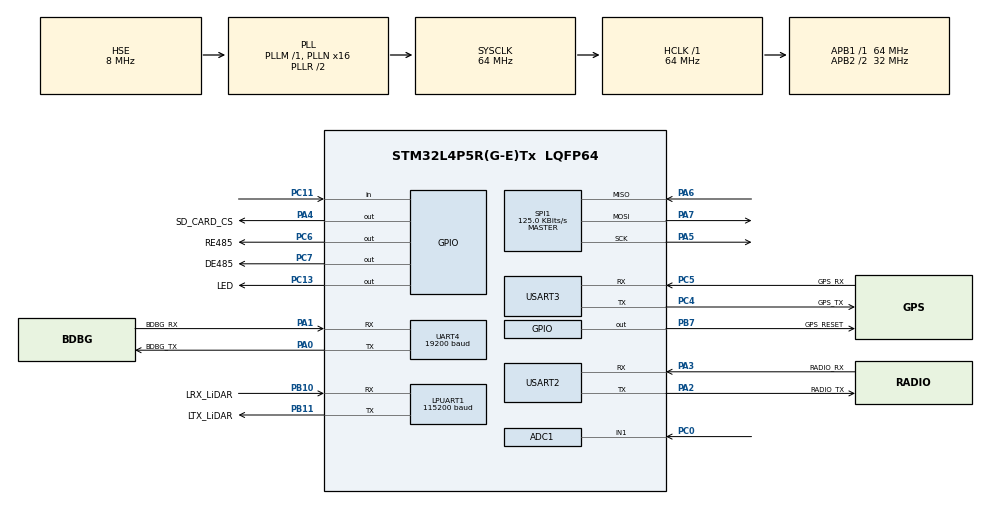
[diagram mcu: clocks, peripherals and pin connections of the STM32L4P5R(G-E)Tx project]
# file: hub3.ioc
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ADC1.Channel-2\#ChannelRegularConversion=ADC_CHANNEL_1
ADC1.NbrOfConversionFlag=1
ADC1.OffsetNumber-2\#ChannelRegularConversion=ADC_OFFSET_NONE
ADC1.Rank-2\#ChannelRegularConversion=1
ADC1.SamplingTime-2\#ChannelRegularConversion=ADC_SAMPLETIME_2CYCLES_5
ADC1.master=1
Dma.LPUART1_RX.2.Direction=DMA_PERIPH_TO_MEMORY
Dma.LPUART1_RX.2.EventEnable=DISABLE
Dma.LPUART1_RX.2.Instance=DMA2_Channel3
Dma.LPUART1_RX.2.MemDataAlignment=DMA_MDATAALIGN_BYTE
Dma.LPUART1_RX.2.MemInc=DMA_MINC_ENABLE
Dma.LPUART1_RX.2.Mode=DMA_CIRCULAR
Dma.LPUART1_RX.2.PeriphDataAlignment=DMA_PDATAALIGN_BYTE
Dma.LPUART1_RX.2.PeriphInc=DMA_PINC_DISABLE
Dma.LPUART1_RX.2.Polarity=HAL_DMAMUX_REQ_GEN_RISING
Dma.LPUART1_RX.2.Priority=DMA_PRIORITY_LOW
Dma.LPUART1_RX.2.RequestNumber=1
Dma.LPUART1_RX.2.SignalID=NONE
Dma.LPUART1_RX.2.SyncEnable=DISABLE
Dma.LPUART1_RX.2.SyncPolarity=HAL_DMAMUX_SYNC_NO_EVENT
Dma.LPUART1_RX.2.SyncRequestNumber=1
Dma.LPUART1_RX.2.SyncSignalID=NONE
Dma.Request0=USART3_RX
Dma.Request1=UART4_RX
Dma.Request2=LPUART1_RX
Dma.Request3=USART2_RX
Dma.UART4_RX.1.Direction=DMA_PERIPH_TO_MEMORY
Dma.UART4_RX.1.EventEnable=DISABLE
Dma.UART4_RX.1.Instance=DMA2_Channel2
Dma.UART4_RX.1.MemDataAlignment=DMA_MDATAALIGN_BYTE
Dma.UART4_RX.1.MemInc=DMA_MINC_ENABLE
Dma.UART4_RX.1.Mode=DMA_NORMAL
Dma.UART4_RX.1.PeriphDataAlignment=DMA_PDATAALIGN_BYTE
Dma.UART4_RX.1.PeriphInc=DMA_PINC_DISABLE
Dma.UART4_RX.1.Polarity=HAL_DMAMUX_REQ_GEN_RISING
Dma.UART4_RX.1.Priority=DMA_PRIORITY_LOW
Dma.UART4_RX.1.RequestNumber=1
Dma.UART4_RX.1.SignalID=NONE
Dma.UART4_RX.1.SyncEnable=DISABLE
Dma.UART4_RX.1.SyncPolarity=HAL_DMAMUX_SYNC_NO_EVENT
Dma.UART4_RX.1.SyncRequestNumber=1
Dma.UART4_RX.1.SyncSignalID=NONE
Dma.USART2_RX.3.Direction=DMA_PERIPH_TO_MEMORY
Dma.USART2_RX.3.EventEnable=DISABLE
Dma.USART2_RX.3.Instance=DMA2_Channel5
Dma.USART2_RX.3.MemDataAlignment=DMA_MDATAALIGN_BYTE
Dma.USART2_RX.3.MemInc=DMA_MINC_ENABLE
Dma.USART2_RX.3.Mode=DMA_CIRCULAR
Dma.USART2_RX.3.PeriphDataAlignment=DMA_PDATAALIGN_BYTE
Dma.USART2_RX.3.PeriphInc=DMA_PINC_DISABLE
Dma.USART2_RX.3.Polarity=HAL_DMAMUX_REQ_GEN_RISING
Dma.USART2_RX.3.Priority=DMA_PRIORITY_LOW
Dma.USART2_RX.3.RequestNumber=1
Dma.USART2_RX.3.SignalID=NONE
Dma.USART2_RX.3.SyncEnable=DISABLE
Dma.USART2_RX.3.SyncPolarity=HAL_DMAMUX_SYNC_NO_EVENT
Dma.USART2_RX.3.SyncRequestNumber=1
Dma.USART2_RX.3.SyncSignalID=NONE
Dma.USART3_RX.0.Direction=DMA_PERIPH_TO_MEMORY
Dma.USART3_RX.0.EventEnable=DISABLE
Dma.USART3_RX.0.Instance=DMA2_Channel1
Dma.USART3_RX.0.MemDataAlignment=DMA_MDATAALIGN_BYTE
Dma.USART3_RX.0.MemInc=DMA_MINC_ENABLE
Dma.USART3_RX.0.Mode=DMA_CIRCULAR
Dma.USART3_RX.0.PeriphDataAlignment=DMA_PDATAALIGN_BYTE
Dma.USART3_RX.0.PeriphInc=DMA_PINC_DISABLE
Dma.USART3_RX.0.Polarity=HAL_DMAMUX_REQ_GEN_RISING
Dma.USART3_RX.0.Priority=DMA_PRIORITY_LOW
Dma.USART3_RX.0.RequestNumber=1
Dma.USART3_RX.0.SignalID=NONE
Dma.USART3_RX.0.SyncEnable=DISABLE
Dma.USART3_RX.0.SyncPolarity=HAL_DMAMUX_SYNC_NO_EVENT
Dma.USART3_RX.0.SyncRequestNumber=1
Dma.USART3_RX.0.SyncSignalID=NONE
LPUART1.BaudRate=115200
LPUART1.WordLength=UART_WORDLENGTH_8B
Mcu.Family=STM32L4
Mcu.Name=STM32L4P5R(G-E)Tx
Mcu.Package=LQFP64
NVIC.DMA2_Channel1_IRQn=true\:0\:0\:false\:false\:true\:false\:true\:true
NVIC.DMA2_Channel2_IRQn=true\:0\:0\:false\:false\:true\:false\:true\:true
NVIC.DMA2_Channel3_IRQn=true\:0\:0\:false\:false\:true\:false\:true\:true
NVIC.DMA2_Channel5_IRQn=true\:0\:0\:false\:false\:true\:false\:true\:true
NVIC.LPUART1_IRQn=true\:0\:0\:false\:false\:true\:true\:true\:true
NVIC.PriorityGroup=NVIC_PRIORITYGROUP_4
NVIC.RTC_WKUP_IRQn=true\:0\:0\:false\:false\:true\:true\:true\:true
NVIC.TIM3_IRQn=true\:0\:0\:false\:false\:true\:true\:true\:true
NVIC.TIM6_DAC_IRQn=true\:1\:0\:true\:false\:true\:true\:true\:true
NVIC.UART4_IRQn=true\:0\:0\:false\:false\:true\:true\:true\:true
NVIC.USART2_IRQn=true\:0\:0\:false\:false\:true\:true\:true\:true
NVIC.USART3_IRQn=true\:0\:0\:false\:false\:true\:true\:true\:true
PA0.GPIO_Label=BDBG_TX
PA0.Mode=Asynchronous
PA0.Signal=UART4_TX
PA1.GPIO_Label=BDBG_RX
PA1.Mode=Asynchronous
PA1.Signal=UART4_RX
PA2.GPIO_Label=RADIO_TX
PA2.Mode=Asynchronous
PA2.Signal=USART2_TX
PA3.GPIO_Label=RADIO_RX
PA3.Mode=Asynchronous
PA3.Signal=USART2_RX
PA4.GPIO_Label=SD_CARD_CS
PA4.GPIO_PuPd=GPIO_PULLUP
PA4.PinState=GPIO_PIN_SET
PA4.Signal=GPIO_Output
PA5.GPIO_PuPd=GPIO_PULLUP
PA5.Mode=Full_Duplex_Master
PA5.Signal=SPI1_SCK
PA6.GPIO_PuPd=GPIO_PULLUP
PA6.Mode=Full_Duplex_Master
PA6.Signal=SPI1_MISO
PA7.GPIO_PuPd=GPIO_PULLUP
PA7.Mode=Full_Duplex_Master
PA7.Signal=SPI1_MOSI
PB10.GPIO_Label=LRX_LiDAR
PB10.Mode=Asynchronous
PB10.Signal=LPUART1_RX
PB11.GPIO_Label=LTX_LiDAR
PB11.Mode=Asynchronous
PB11.Signal=LPUART1_TX
PB7.GPIO_Label=GPS_RESET
PB7.Signal=GPIO_Output
PC0.Signal=ADCx_IN1
PC11.Signal=GPIO_Input
PC13.GPIO_Label=LED
PC13.Signal=GPIO_Output
PC4.GPIO_Label=GPS_TX
PC4.Mode=Asynchronous
PC4.Signal=USART3_TX
PC5.GPIO_Label=GPS_RX
PC5.Mode=Asynchronous
PC5.Signal=USART3_RX
PC6.GPIO_Label=RE485
PC6.Signal=GPIO_Output
PC7.GPIO_Label=DE485
PC7.Signal=GPIO_Output
PH0-OSC_IN\ (PH0).Mode=HSE-External-Oscillator
PH0-OSC_IN\ (PH0).Signal=RCC_OSC_IN
PH1-OSC_OUT\ (PH1).Mode=HSE-External-Oscillator
PH1-OSC_OUT\ (PH1).Signal=RCC_OSC_OUT
ProjectManager.HeapSize=0x8000
ProjectManager.StackSize=0x8000
ProjectManager.TargetToolchain=MDK-ARM V5.32
RCC.ADCFreq_Value=32000000
RCC.AHBFreq_Value=64000000
RCC.APB1Freq_Value=64000000
RCC.APB1TimFreq_Value=64000000
RCC.APB2CLKDivider=RCC_HCLK_DIV2
RCC.APB2Freq_Value=32000000
RCC.APB2TimFreq_Value=64000000
RCC.CortexFreq_Value=64000000
RCC.HCLKFreq_Value=64000000
RCC.HSE_VALUE=8000000
RCC.HSI48_VALUE=48000000
RCC.HSI_VALUE=16000000
RCC.LSE_VALUE=32768
RCC.MSI_VALUE=4000000
RCC.PLLN=16
RCC.PLLSourceVirtual=RCC_PLLSOURCE_HSE
RCC.SYSCLKFreq_VALUE=64000000
RCC.SYSCLKSource=RCC_SYSCLKSOURCE_PLLCLK
RCC.USBFreq_Value=32000000
RCC.VCOOutputFreq_Value=128000000
RTC.WakeUpClock-WakeUp=RTC_WAKEUPCLOCK_CK_SPRE_16BITS
RTC.WakeUpCounter-WakeUp=59
SH.ADCx_IN1.0=ADC1_IN1,IN1-Single-Ended
SPI1.BaudRatePrescaler=SPI_BAUDRATEPRESCALER_256
SPI1.CalculateBaudRate=125.0 KBits/s
SPI1.DataSize=SPI_DATASIZE_8BIT
SPI1.Direction=SPI_DIRECTION_2LINES
SPI1.Mode=SPI_MODE_MASTER
SPI1.VirtualType=VM_MASTER
TIM3.Period=4999
TIM3.Prescaler=63999
TIM6.Period=99
TIM6.Prescaler=63999
UART4.BaudRate=19200
USART2.VirtualMode-Asynchronous=VM_ASYNC
USART3.VirtualMode-Asynchronous=VM_ASYNC
VP_FATFS_VS_Generic.Mode=User_defined
VP_RTC_VS_RTC_Activate.Mode=RTC_Enabled
VP_RTC_VS_RTC_Calendar.Mode=RTC_Calendar
VP_RTC_VS_RTC_WakeUp_intern.Mode=WakeUp
VP_TIM3_VS_ClockSourceINT.Mode=Internal
VP_TIM3_VS_OPM.Mode=OPM_bit
VP_TIM6_VS_ClockSourceINT.Mode=Enable_Timer
board=custom

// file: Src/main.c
/* USER CODE BEGIN Header */
/**
  ******************************************************************************
  * @file           : main.c
  * @brief          : Main program body
  ******************************************************************************
  * @attention
  *
  * Copyright (c) 2026 STMicroelectronics.
  * All rights reserved.
  *
  * This software is licensed under terms that can be found in the LICENSE file
  * in the root directory of this software component.
  * If no LICENSE file comes with this software, it is provided AS-IS.
  *
  ******************************************************************************
  */
/* USER CODE END Header */
#include "main.h"
#include "fatfs.h"

/* USER CODE BEGIN Includes */
#include <string.h>
#include <stdio.h>
#include "logger_types.h"
#include "logger_state_machine.h"
#include "gps.h"
#include "lidar.h"
#include "bdbg.h"
#include "bdbg_config.h"
#include "sd_logger.h"

/* USER CODE END Includes */

/* USER CODE BEGIN PD */

/*
 * Параметры первичной проверки аккумулятора.
 *
 * Напряжения указаны непосредственно на входе ADC1 (PC1),
 * до пересчёта через делитель напряжения.
 */
#define BATTERY_ADC_REFERENCE_V       2.5f
#define BATTERY_ADC_MAX_VALUE         4095.0f
#define BATTERY_STARTUP_SAMPLES       10U

#define BATTERY_THRESHOLD_33_V        0.824f
#define BATTERY_THRESHOLD_66_V        0.855f
#define BATTERY_THRESHOLD_100_V       0.915f

/* Максимальное ожидание одного преобразования ADC, мс. */
#define BATTERY_ADC_TIMEOUT_MS        100U

/* Время отображения результатов первичной проверки, мс. */
#define STARTUP_INDICATION_TIME_MS    60000U

/* USER CODE END PD */

ADC_HandleTypeDef hadc1;
DMA_HandleTypeDef hdma_adc1;

UART_HandleTypeDef hlpuart1;
UART_HandleTypeDef huart4;
UART_HandleTypeDef huart2;
UART_HandleTypeDef huart3;
DMA_HandleTypeDef hdma_lpuart1_rx;
DMA_HandleTypeDef hdma_uart4_rx;
DMA_HandleTypeDef hdma_usart2_rx;
DMA_HandleTypeDef hdma_usart3_rx;

RTC_HandleTypeDef hrtc;

SPI_HandleTypeDef hspi1;

TIM_HandleTypeDef htim3;
TIM_HandleTypeDef htim6;

/* USER CODE BEGIN PV */
uint16_t adc_value=0;

/*
 * ============================================================
 * РАБОЧИЕ ИЗМЕРЕНИЯ АККУМУЛЯТОРА
 * ============================================================
 *
 * Эти переменные используются для обмена данными
 * между прерыванием ADC1 и основной стейт-машиной.
 *
 * В отличие от первоначальной проверки аккумулятора,
 * рабочие измерения выполняются без блокирующего
 * ожидания завершения преобразования.
 */

/*
 * Результат последнего завершённого преобразования ADC1.
 *
 * Записывается обработчиком прерывания ADC.
 * Читается основной стейт-машиной.
 */
volatile uint16_t battery_adc_raw = 0U;

/*
 * Признак готовности очередного результата ADC.
 *
 * 0 — нового результата нет.
 * 1 — результат доступен в battery_adc_raw.
 *
 * После обработки результата флаг сбрасывается
 * основной стейт-машиной.
 */
volatile uint8_t battery_adc_ready = 0U;

/*
 * Признак ошибки ADC1.
 *
 * 0 — ошибка не зарегистрирована.
 * 1 — произошла ошибка ADC.
 *
 * Обработчик прерывания только устанавливает флаг.
 * Решение о переходе в BATTERY_ERROR_PROC
 * принимает основная стейт-машина.
 */
volatile uint8_t battery_adc_error = 0U;

/*
 * Разрешение обработки результатов рабочего
 * измерения аккумулятора.
 *
 * 0 — рабочее измерение не выполняется.
 * 1 — ADC используется состояниями аккумулятора.
 *
 * Это позволяет отделить рабочие измерения
 * от первоначальной проверки при запуске LOGGER.
 */
volatile uint8_t battery_adc_active = 0U;

/*
 * Основной объект стейт-машины LOGGER.
 * Содержит текущее состояние всей логики программы.
 */
LoggerStateMachine logger;

/*
 * Глобальный счётчик секунд RTC.
 *
 * Увеличивается на единицу при каждом прерывании
 * RTC WakeUp Timer (период 1 секунда).
 *
 * Значение никогда не обнуляется программой.
 * Основная стейт-машина только читает счётчик.
 *
 * volatile необходим, поскольку счётчик изменяется
 * в обработчике прерывания RTC.
 */
volatile uint32_t rtc_seconds = 0U;

/*
 * Размер DMA-буфера приёма USART2 (RadioLine).
 *
 * В этот буфер DMA непосредственно записывает байты,
 * поступающие по USART2.
 */
#define RADIOLINE_DMA_RX_BUFFER_SIZE    256U

/*
 * Размер общего буфера RadioLine.
 *
 * В него будем последовательно накапливать весь burst:
 * один пакет либо несколько подряд идущих копий пакета.
 *
 * Конкретный размер позже при необходимости скорректируем
 * по максимальному размеру команды протокола.
 */
#define RADIOLINE_RX_BUFFER_SIZE        2048U

/*
 * Рабочий буфер DMA для USART2.
 *
 * HAL_UARTEx_ReceiveToIdle_DMA() будет принимать сюда
 * очередную порцию данных от RadioLine.
 */
static uint8_t radioline_dma_rx_buffer[RADIOLINE_DMA_RX_BUFFER_SIZE];

/*
 * Общий накопительный буфер RadioLine.
 * После каждого события приёма данные из DMA-буфера
 * будут добавляться сюда. После 100 мс тишины этот
 * буфер будет готов к обработке в COMMAND_INFO.
 */
uint8_t radioline_rx_buffer[RADIOLINE_RX_BUFFER_SIZE];

/*
 * Текущее количество принятых байтов в общем
 * накопительном буфере RadioLine.
 */
volatile uint16_t radioline_rx_length = 0U;

/*
 * Флаг завершения приёма burst RadioLine.
 *
 * 0 - burst ещё принимается;
 * 1 - после последнего принятого байта прошло 100 мс.
 */
volatile uint8_t com_info = 0U;

/*
 * ============================================================================
 * Флаг срабатывания общего таймера контроля ответа прибора TIM3.
 *
 * TIM3 используется для ограничения времени ожидания ответа
 * от текущего прибора.
 *
 * Сам callback таймера НЕ принимает никаких решений и НЕ изменяет
 * состояние LOGGER. Он только устанавливает этот флаг.
 *
 * Обработка таймаута выполняется позже основной стейт-машиной,
 * которая по logger->dev_type определяет, ответ какого прибора ожидался.
 *
 * volatile необходим, поскольку значение изменяется из прерывания,
 * а читается из основного цикла программы.
 *
 * 0 - таймаут не произошёл;
 * 1 - время ожидания ответа прибора истекло.
 * ============================================================================
 */
volatile uint8_t device_timeout = 0U;

/* Буферы и управление GPS вынесены в gps.c. */

/* USER CODE END PV */

void SystemClock_Config(void);
static void MX_GPIO_Init(void);
static void MX_DMA_Init(void);
static void MX_USART3_UART_Init(void);
static void MX_USART2_UART_Init(void);
static void MX_SPI1_Init(void);
static void MX_ADC1_Init(void);
static void MX_UART4_Init(void);
static void MX_LPUART1_UART_Init(void);
static void MX_RTC_Init(void);
static void MX_TIM6_Init(void);
static void MX_TIM3_Init(void);
/* USER CODE BEGIN PFP */
/*
*/

#include <string.h>
#include <stdint.h>

void HAL_UARTEx_RxEventCallback(UART_HandleTypeDef *huart, uint16_t Size)
{
    /*
		 * Общий callback приёма данных UART.
		 *
		 * USART2 — приём команд RadioLine.
		 * USART3 — приём данных GPS.
		 *
		 * Обработка каждого интерфейса выполняется
		 * независимо от остальных.
		 */

		/*
		* Последняя обработанная позиция в циклическом DMA-буфере USART2.
		*
		* DMA USART2 работает в режиме DMA_CIRCULAR.
		* Поэтому после события IDLE DMA не перезапускается, а продолжает
		* записывать следующие байты дальше в radioline_dma_rx_buffer.
		*
		* Эта переменная позволяет определить, какие именно байты появились
		* с момента предыдущего вызова HAL_UARTEx_RxEventCallback().
		*/
		static uint16_t radioline_dma_old_pos = 0U;

		if (huart->Instance == USART2)
		{
				/*
				 * USART2 RX DMA работает в режиме DMA_CIRCULAR.
				 *
				 * В этом режиме параметр Size НЕ является просто размером
				 * очередной независимой порции данных.
				 *
				 * Size указывает текущую позицию DMA в циклическом буфере:
				 * данные доступны до позиции Size.
				 *
				 * Поэтому необходимо копировать только те байты,
				 * которые появились после предыдущего вызова callback.
				 */

				uint16_t new_data_length = 0U;

				/*
				 * СЛУЧАЙ 1.
				 *
				 * DMA ещё не дошёл до конца буфера.
				 *
				 * Например:
				 *
				 * radioline_dma_old_pos = 0
				 * Size                  = 14
				 *
				 * Значит новые данные находятся:
				 *
				 * radioline_dma_rx_buffer[0 ... 13]
				 */
				if (Size > radioline_dma_old_pos)
				{
						new_data_length = Size - radioline_dma_old_pos;

						/*
						 * Проверяем, помещаются ли новые данные
						 * в накопительный буфер RadioLine.
						 */
						if ((radioline_rx_length + new_data_length) <=
								RADIOLINE_RX_BUFFER_SIZE)
						{
								memcpy(&radioline_rx_buffer[radioline_rx_length],
											 &radioline_dma_rx_buffer[radioline_dma_old_pos],
											 new_data_length);

								radioline_rx_length += new_data_length;
						}
				}

				/*
				 * СЛУЧАЙ 2.
				 *
				 * DMA дошёл до конца циклического буфера и начал запись
				 * снова с его начала.
				 *
				 * Например:
				 *
				 * старая позиция = 250
				 * новая Size     = 10
				 *
				 * Тогда новые данные расположены двумя участками:
				 *
				 * [250 ... 255]
				 *
				 * и
				 *
				 * [0 ... 9]
				 */
				else if (Size < radioline_dma_old_pos)
				{
						uint16_t tail_length =
								RADIOLINE_DMA_RX_BUFFER_SIZE - radioline_dma_old_pos;

						uint16_t head_length = Size;

						new_data_length = tail_length + head_length;

						/*
						 * Проверяем место сразу для обоих участков,
						 * чтобы не записать только половину новых данных.
						 */
						if ((radioline_rx_length + new_data_length) <=
								RADIOLINE_RX_BUFFER_SIZE)
						{
								/*
								 * Сначала копируем остаток данных
								 * от старой позиции до конца DMA-буфера.
								 */
								if (tail_length > 0U)
								{
										memcpy(&radioline_rx_buffer[radioline_rx_length],
													 &radioline_dma_rx_buffer[radioline_dma_old_pos],
													 tail_length);

										radioline_rx_length += tail_length;
								}

								/*
								 * Затем копируем данные, которые DMA уже записал
								 * с начала циклического буфера.
								 */
								if (head_length > 0U)
								{
										memcpy(&radioline_rx_buffer[radioline_rx_length],
													 &radioline_dma_rx_buffer[0],
													 head_length);

										radioline_rx_length += head_length;
								}
						}
				}

				/*
				 * Запоминаем текущую позицию DMA.
				 *
				 * Особый случай Size == RADIOLINE_DMA_RX_BUFFER_SIZE:
				 * DMA дошёл до конца буфера и в circular mode следующая запись
				 * начнётся снова с позиции 0.
				 */
				if (Size >= RADIOLINE_DMA_RX_BUFFER_SIZE)
				{
						radioline_dma_old_pos = 0U;
				}
				else
				{
						radioline_dma_old_pos = Size;
				}

				/*
				 * Таймер 100 мс перезапускаем только тогда,
				 * когда действительно появились новые данные.
				 *
				 * TIM6 используется для определения окончания
				 * сообщения RadioLine по паузе.
				 */
				if (new_data_length > 0U)
				{
						/*
						 * Останавливаем предыдущий отсчёт.
						 */
						HAL_TIM_Base_Stop_IT(&htim6);

						/*
						 * Начинаем отсчёт 100 мс заново.
						 */
						__HAL_TIM_SET_COUNTER(&htim6, 0U);

						HAL_TIM_Base_Start_IT(&htim6);
				}

				/*
				 * ВАЖНО:
				 *
				 * HAL_UARTEx_ReceiveToIdle_DMA() здесь НЕ вызываем.
				 *
				 * USART2 RX DMA настроен в DMA_CIRCULAR.
				 * После IDLE DMA автоматически продолжает работать.
				 *
				 * Повторный вызов HAL_UARTEx_ReceiveToIdle_DMA()
				 * здесь привёл бы к HAL_BUSY, потому что текущий
				 * DMA-приём всё ещё активен.
				 */
		}

    /* GPS: ISR только переносит данные; разбор NMEA выполняется в main loop. */
    if (huart->Instance == USART3)
    {
        GPS_RxEventCallback(Size);
        return;
    }

    /* UART4: событие приёма ответа БДБГ (IDLE или заполнение буфера). */
    if (huart->Instance == UART4)
    {
        BDBG_RxEventCallback(huart, Size);
        return;
    }

}

/* Ошибки GPS USART3 сигнализируем стейт-машине без блокировки в ISR. */
/* DMA normal mode: событие полного приёма БДБГ. */
void HAL_UART_ErrorCallback(UART_HandleTypeDef *huart)
{
    if (huart->Instance == UART4) { BDBG_UartErrorCallback(huart); return; }
    if (huart->Instance == USART3)
        GPS_NotifyUartError();

		/*
		 * Ошибка приёма данных LIDAR через LPUART1.
		 * Сообщаем модулю LIDAR о неисправности текущего приёма.
		 */
		if (huart->Instance == LPUART1)
		{
				LIDAR_NotifyUartError();
				return;
		}

}

void HAL_TIM_PeriodElapsedCallback(TIM_HandleTypeDef *htim)
{
    /*
     * ========================================================================
     * TIM6
     * ========================================================================
     *
     * Таймер окончания burst RadioLine.
     *
     * Если после последнего принятого байта RadioLine прошло 100 мс,
     * считаем текущий burst завершённым.
     *
     * Эту существующую логику не изменяем.
     */
    if (htim->Instance == TIM6)
    {
        /*
         * Останавливаем TIM6.
         *
         * Следующий запуск произойдёт после поступления новых данных
         * RadioLine.
         */
        HAL_TIM_Base_Stop_IT(&htim6);

        /*
         * Сообщаем основному циклу, что накопленный burst RadioLine
         * готов к обработке.
         */
        com_info = 1U;

        return;
    }

    /*
     * ========================================================================
     * TIM3
     * ========================================================================
     *
     * Общий таймер контроля времени ожидания ответа прибора.
     *
     * TIM3 настроен в One Pulse Mode, поэтому после истечения заданного
     * интервала используется как одноразовое событие таймаута.
     *
     * ВАЖНО:
     *
     * В прерывании:
     *
     * - НЕ определяем тип прибора;
     * - НЕ изменяем logger->state;
     * - НЕ отправляем пакеты RadioLine;
     * - НЕ выполняем обработку ошибки;
     * - НЕ запускаем стейт-машину.
     *
     * Callback только сообщает основной программе о том, что время
     * ожидания ответа текущего прибора истекло.
     *
     * Какой прибор ожидался, основная стейт-машина определит
     * по logger->dev_type.
     */
    if (htim->Instance == TIM3)
    {
        /*
         * Фиксируем событие таймаута.
         */
        device_timeout = 1U;

        return;
    }
}

/* USER CODE END PFP */

/* USER CODE BEGIN 0 */

/*
 * ============================================================
 * Первичная проверка аккумулятора при включении LOGGER.
 *
 * Выполняется один раз до входа в while(1).
 *
 * Возвращает:
 * 1 — измерение успешно;
 * 0 — ошибка ADC.
 *
 * Измеренное напряжение на входе ADC возвращается
 * через указатель voltage.
 *
 * Функция блокирующая. Это допустимо исключительно
 * на этапе первоначальной проверки.
 * ============================================================
 */
static uint8_t Battery_StartupMeasure(float *voltage)
{
    uint32_t adc_sum = 0U;
    uint32_t adc_raw = 0U;

    if (voltage == NULL)
    {
        return 0U;
    }

    *voltage = 0.0f;

    /*
     * Калибровка ADC1 перед первым измерением.
     * ADC должен быть остановлен.
     */
    if (HAL_ADCEx_Calibration_Start(
            &hadc1,
            ADC_SINGLE_ENDED) != HAL_OK)
    {
        return 0U;
    }

    /*
     * Последовательно выполняем 10 преобразований.
     */
    for (uint32_t i = 0U; i < BATTERY_STARTUP_SAMPLES; i++)
    {
        /* Запускаем одно преобразование ADC. */
        if (HAL_ADC_Start(&hadc1) != HAL_OK)
        {
            (void)HAL_ADC_Stop(&hadc1);
            return 0U;
        }

        /*
         * Ожидаем завершения преобразования.
         * Ожидание ограничено таймаутом.
         */
        if (HAL_ADC_PollForConversion(
                &hadc1,
                BATTERY_ADC_TIMEOUT_MS) != HAL_OK)
        {
            (void)HAL_ADC_Stop(&hadc1);
            return 0U;
        }

        /* Получаем 12-битный результат измерения. */
        adc_raw = HAL_ADC_GetValue(&hadc1);

        /* Добавляем результат к общей сумме. */
        adc_sum += adc_raw;

        /* Останавливаем ADC перед следующим запуском. */
        if (HAL_ADC_Stop(&hadc1) != HAL_OK)
        {
            return 0U;
        }
    }

    /*
     * Вычисляем среднее напряжение на входе ADC:
     *
     * U = SUM(raw) / 10 * 2.5 / 4095
     *
     * Промежуточное усреднение выполняется без
     * целочисленного округления.
     */
    *voltage =
        ((float)adc_sum * BATTERY_ADC_REFERENCE_V) /
        ((float)BATTERY_STARTUP_SAMPLES *
         BATTERY_ADC_MAX_VALUE);

    return 1U;
}

/*
 * ============================================================
 * Отображение уровня аккумулятора на трёх светодиодах.
 *
 * PA15 — 33%.
 * PA12 — 66%.
 * PA11 — 100%.
 *
 * voltage — напряжение непосредственно на входе ADC1.
 *
 * При напряжении ниже 0.824 В все светодиоды выключены.
 * ============================================================
 */
static void Battery_StartupShowLevel(float voltage)
{
    /*
     * Сначала выключаем все три светодиода.
     * Это исключает сохранение предыдущей индикации.
     */
    HAL_GPIO_WritePin(
        GPIOA,
        GPIO_PIN_11 | GPIO_PIN_12 | GPIO_PIN_15,
        GPIO_PIN_RESET
    );

    /*
     * Уровень 100%:
     * включаем все три светодиода.
     */
    if (voltage >= BATTERY_THRESHOLD_100_V)
    {
        HAL_GPIO_WritePin(
            GPIOA,
            GPIO_PIN_11 | GPIO_PIN_12 | GPIO_PIN_15,
            GPIO_PIN_SET
        );
    }
    /*
     * Уровень 66%:
     * включаем PA15 и PA12.
     */
    else if (voltage >= BATTERY_THRESHOLD_66_V)
    {
        HAL_GPIO_WritePin(
            GPIOA,
            GPIO_PIN_15 | GPIO_PIN_12,
            GPIO_PIN_SET
        );
    }
    /*
     * Уровень 33%:
     * включаем только PA15.
     */
    else if (voltage >= BATTERY_THRESHOLD_33_V)
    {
        HAL_GPIO_WritePin(
            GPIOA,
            GPIO_PIN_15,
            GPIO_PIN_SET
        );
    }

    /*
     * При voltage < 0.824 В ничего не включаем.
     */
}

/* USER CODE END 0 */

int main(void)
{
    /* USER CODE BEGIN 1 */

    /*
     * Напряжение на входе ADC1 после усреднения.
     */
    float startup_battery_voltage = 0.0f;

    /*
     * Результат первичного измерения аккумулятора.
     */
    uint8_t startup_battery_ok = 0U;

    /* USER CODE END 1 */

    /* MCU Configuration */

    HAL_Init();

    SystemClock_Config();

    /*
     * Инициализация периферии STM32.
     */
    MX_GPIO_Init();
    MX_DMA_Init();
    MX_USART3_UART_Init();
    MX_USART2_UART_Init();
    MX_SPI1_Init();
    MX_FATFS_Init();
    MX_ADC1_Init();
    MX_UART4_Init();
    MX_LPUART1_UART_Init();
    MX_RTC_Init();
    MX_TIM6_Init();
    MX_TIM3_Init();

    /* USER CODE BEGIN 2 */

    /*
     * ========================================================
     * Инициализация SD-карты.
     * ========================================================
     */

    SD_Logger_Init();

    /*
     * Монтирование SD-карты.
     *
     * FR_OK означает, что файловая система доступна.
     */
    FRESULT sd_mount_result =
        f_mount(&USERFatFS, USERPath, 1U);

    /*
     * Сохраняем результат для последующей работы
     * модуля SD_Logger и стейт-машины.
     */
    SD_Logger_SetMountResult(sd_mount_result);

    /*
     * ========================================================
     * Инициализация программных модулей LOGGER.
     * ========================================================
     */

    LoggerStateMachine_Init(&logger);

    GPS_Init();

    LIDAR_Init();

    BDBG_Init();

    /*
     * Управление сигналом сброса GPS.
     * Существующую логику сохраняем.
     */
#ifdef DEBUG_MODE
    HAL_GPIO_WritePin(
        GPS_RESET_GPIO_Port,
        GPS_RESET_Pin,
        GPIO_PIN_RESET
    );
#else
    HAL_GPIO_WritePin(
        GPS_RESET_GPIO_Port,
        GPS_RESET_Pin,
        GPIO_PIN_SET
    );
#endif

    /*
     * ========================================================
     * Первичная проверка аккумулятора.
     * ========================================================
     *
     * Выполняется один раз после включения питания.
     * Измеряем напряжение 10 раз и вычисляем среднее.
     */

    startup_battery_ok =
        Battery_StartupMeasure(&startup_battery_voltage);

    /*
     * При успешном измерении отображаем уровень заряда.
     *
     * При ошибке ADC все три светодиода остаются
     * выключенными.
     */
    if (startup_battery_ok != 0U)
    {
        Battery_StartupShowLevel(startup_battery_voltage);
    }
    else
    {
        HAL_GPIO_WritePin(
            GPIOA,
            GPIO_PIN_11 | GPIO_PIN_12 | GPIO_PIN_15,
            GPIO_PIN_RESET
        );
    }

    /*
     * ========================================================
     * Первичная индикация SD-карты.
     * ========================================================
     *
     * PC13 = 1 — монтирование успешно.
     * PC13 = 0 — монтирование завершилось ошибкой.
     */

    HAL_GPIO_WritePin(
        LED_GPIO_Port,
        LED_Pin,
        (sd_mount_result == FR_OK)
            ? GPIO_PIN_SET
            : GPIO_PIN_RESET
    );

    /*
     * ========================================================
     * Время визуального контроля — 60 секунд.
     * ========================================================
     *
     * Оператор проверяет индикацию аккумулятора
     * и наличие SD-карты.
     *
     * При необходимости питание LOGGER можно отключить
     * для замены аккумулятора или установки SD-карты.
     *
     * Главная стейт-машина ещё не запущена.
     */
    HAL_Delay(STARTUP_INDICATION_TIME_MS);

    /*
     * ========================================================
     * Завершение первоначальной проверки.
     * ========================================================
     *
     * Выключаем все четыре светодиода.
     */

    HAL_GPIO_WritePin(
        GPIOA,
        GPIO_PIN_11 | GPIO_PIN_12 | GPIO_PIN_15,
        GPIO_PIN_RESET
    );

    HAL_GPIO_WritePin(
        LED_GPIO_Port,
        LED_Pin,
        GPIO_PIN_RESET
    );

    /*
     * ========================================================
     * Запуск постоянного приёма RadioLine через USART2 DMA.
     * ========================================================
     *
     * Выполняется после завершения первичной проверки.
     */

    if (HAL_UARTEx_ReceiveToIdle_DMA(
            &huart2,
            radioline_dma_rx_buffer,
            RADIOLINE_DMA_RX_BUFFER_SIZE) != HAL_OK)
    {
        Error_Handler();
    }

    /*
     * Отключаем прерывание по половине DMA-буфера.
     */
    __HAL_DMA_DISABLE_IT(
        huart2.hdmarx,
        DMA_IT_HT
    );

    /* USER CODE END 2 */

    /* Infinite loop */

    while (1)
    {

        /* USER CODE BEGIN 3 */

        /*
         * Выполняем один шаг основной стейт-машины.
         */
        LoggerStateMachine_Process(&logger);

    }

    /* USER CODE END 3 */
}

void SystemClock_Config(void)
{
  RCC_OscInitTypeDef RCC_OscInitStruct = {0};
  RCC_ClkInitTypeDef RCC_ClkInitStruct = {0};

  /** Configure the main internal regulator output voltage
  */
  if (HAL_PWREx_ControlVoltageScaling(PWR_REGULATOR_VOLTAGE_SCALE1) != HAL_OK)
  {
    Error_Handler();
  }

  /** Initializes the RCC Oscillators according to the specified parameters
  * in the RCC_OscInitTypeDef structure.
  */
  RCC_OscInitStruct.OscillatorType = RCC_OSCILLATORTYPE_LSI|RCC_OSCILLATORTYPE_HSE;
  RCC_OscInitStruct.HSEState = RCC_HSE_ON;
  RCC_OscInitStruct.LSIState = RCC_LSI_ON;
  RCC_OscInitStruct.PLL.PLLState = RCC_PLL_ON;
  RCC_OscInitStruct.PLL.PLLSource = RCC_PLLSOURCE_HSE;
  RCC_OscInitStruct.PLL.PLLM = 1;
  RCC_OscInitStruct.PLL.PLLN = 16;
  RCC_OscInitStruct.PLL.PLLP = RCC_PLLP_DIV2;
  RCC_OscInitStruct.PLL.PLLQ = RCC_PLLQ_DIV2;
  RCC_OscInitStruct.PLL.PLLR = RCC_PLLR_DIV2;
  if (HAL_RCC_OscConfig(&RCC_OscInitStruct) != HAL_OK)
  {
    Error_Handler();
  }

  /** Initializes the CPU, AHB and APB buses clocks
  */
  RCC_ClkInitStruct.ClockType = RCC_CLOCKTYPE_HCLK|RCC_CLOCKTYPE_SYSCLK
                              |RCC_CLOCKTYPE_PCLK1|RCC_CLOCKTYPE_PCLK2;
  RCC_ClkInitStruct.SYSCLKSource = RCC_SYSCLKSOURCE_PLLCLK;
  RCC_ClkInitStruct.AHBCLKDivider = RCC_SYSCLK_DIV1;
  RCC_ClkInitStruct.APB1CLKDivider = RCC_HCLK_DIV1;
  RCC_ClkInitStruct.APB2CLKDivider = RCC_HCLK_DIV2;

  if (HAL_RCC_ClockConfig(&RCC_ClkInitStruct, FLASH_LATENCY_3) != HAL_OK)
  {
    Error_Handler();
  }
}

static void MX_ADC1_Init(void)
{

  ADC_MultiModeTypeDef multimode = {0};
  ADC_ChannelConfTypeDef sConfig = {0};

  /** Common config
  */
  hadc1.Instance = ADC1;
  hadc1.Init.ClockPrescaler = ADC_CLOCK_ASYNC_DIV1;
  hadc1.Init.Resolution = ADC_RESOLUTION_12B;
  hadc1.Init.DataAlign = ADC_DATAALIGN_RIGHT;
  hadc1.Init.ScanConvMode = ADC_SCAN_DISABLE;
  hadc1.Init.EOCSelection = ADC_EOC_SINGLE_CONV;
  hadc1.Init.LowPowerAutoWait = DISABLE;
  hadc1.Init.ContinuousConvMode = DISABLE;
  hadc1.Init.NbrOfConversion = 1;
  hadc1.Init.DiscontinuousConvMode = DISABLE;
  hadc1.Init.ExternalTrigConv = ADC_SOFTWARE_START;
  hadc1.Init.ExternalTrigConvEdge = ADC_EXTERNALTRIGCONVEDGE_NONE;
  hadc1.Init.DMAContinuousRequests = DISABLE;
  hadc1.Init.Overrun = ADC_OVR_DATA_PRESERVED;
  hadc1.Init.OversamplingMode = DISABLE;
  if (HAL_ADC_Init(&hadc1) != HAL_OK)
  {
    Error_Handler();
  }

  /** Configure the ADC multi-mode
  */
  multimode.Mode = ADC_MODE_INDEPENDENT;
  if (HAL_ADCEx_MultiModeConfigChannel(&hadc1, &multimode) != HAL_OK)
  {
    Error_Handler();
  }

  /** Configure Regular Channel
  */
  sConfig.Channel = ADC_CHANNEL_1;
  sConfig.Rank = ADC_REGULAR_RANK_1;
  sConfig.SamplingTime = ADC_SAMPLETIME_640CYCLES_5;
  sConfig.SingleDiff = ADC_SINGLE_ENDED;
  sConfig.OffsetNumber = ADC_OFFSET_NONE;
  sConfig.Offset = 0;
  if (HAL_ADC_ConfigChannel(&hadc1, &sConfig) != HAL_OK)
  {
    Error_Handler();
  }

}

static void MX_LPUART1_UART_Init(void)
{

  hlpuart1.Instance = LPUART1;
  hlpuart1.Init.BaudRate = 115200;
  hlpuart1.Init.WordLength = UART_WORDLENGTH_8B;
  hlpuart1.Init.StopBits = UART_STOPBITS_1;
  hlpuart1.Init.Parity = UART_PARITY_NONE;
  hlpuart1.Init.Mode = UART_MODE_TX_RX;
  hlpuart1.Init.HwFlowCtl = UART_HWCONTROL_NONE;
  hlpuart1.Init.OneBitSampling = UART_ONE_BIT_SAMPLE_DISABLE;
  hlpuart1.Init.ClockPrescaler = UART_PRESCALER_DIV1;
  hlpuart1.AdvancedInit.AdvFeatureInit = UART_ADVFEATURE_NO_INIT;
  hlpuart1.FifoMode = UART_FIFOMODE_DISABLE;
  if (HAL_UART_Init(&hlpuart1) != HAL_OK)
  {
    Error_Handler();
  }
  if (HAL_UARTEx_SetTxFifoThreshold(&hlpuart1, UART_TXFIFO_THRESHOLD_1_8) != HAL_OK)
  {
    Error_Handler();
  }
  if (HAL_UARTEx_SetRxFifoThreshold(&hlpuart1, UART_RXFIFO_THRESHOLD_1_8) != HAL_OK)
  {
    Error_Handler();
  }
  if (HAL_UARTEx_DisableFifoMode(&hlpuart1) != HAL_OK)
  {
    Error_Handler();
  }

}

static void MX_UART4_Init(void)
{

  huart4.Instance = UART4;
  huart4.Init.BaudRate = BDBG_UART_BAUDRATE;
  huart4.Init.WordLength = BDBG_UART_WORD_LENGTH;
  huart4.Init.StopBits = BDBG_UART_STOP_BITS;
  huart4.Init.Parity = BDBG_UART_PARITY;
  huart4.Init.Mode = UART_MODE_TX_RX;
  huart4.Init.HwFlowCtl = UART_HWCONTROL_NONE;
  huart4.Init.OverSampling = UART_OVERSAMPLING_16;
  huart4.Init.OneBitSampling = UART_ONE_BIT_SAMPLE_DISABLE;
  huart4.Init.ClockPrescaler = UART_PRESCALER_DIV1;
  huart4.AdvancedInit.AdvFeatureInit = UART_ADVFEATURE_NO_INIT;
  if (HAL_UART_Init(&huart4) != HAL_OK)
  {
    Error_Handler();
  }
  if (HAL_UARTEx_SetTxFifoThreshold(&huart4, UART_TXFIFO_THRESHOLD_1_8) != HAL_OK)
  {
    Error_Handler();
  }
  if (HAL_UARTEx_SetRxFifoThreshold(&huart4, UART_RXFIFO_THRESHOLD_1_8) != HAL_OK)
  {
    Error_Handler();
  }
  if (HAL_UARTEx_DisableFifoMode(&huart4) != HAL_OK)
  {
    Error_Handler();
  }

}

static void MX_USART2_UART_Init(void)
{

  huart2.Instance = USART2;
  huart2.Init.BaudRate = 115200;
  huart2.Init.WordLength = UART_WORDLENGTH_8B;
  huart2.Init.StopBits = UART_STOPBITS_1;
  huart2.Init.Parity = UART_PARITY_NONE;
  huart2.Init.Mode = UART_MODE_TX_RX;
  huart2.Init.HwFlowCtl = UART_HWCONTROL_NONE;
  huart2.Init.OverSampling = UART_OVERSAMPLING_16;
  huart2.Init.OneBitSampling = UART_ONE_BIT_SAMPLE_DISABLE;
  huart2.Init.ClockPrescaler = UART_PRESCALER_DIV1;
  huart2.AdvancedInit.AdvFeatureInit = UART_ADVFEATURE_NO_INIT;
  if (HAL_UART_Init(&huart2) != HAL_OK)
  {
    Error_Handler();
  }
  if (HAL_UARTEx_SetTxFifoThreshold(&huart2, UART_TXFIFO_THRESHOLD_1_8) != HAL_OK)
  {
    Error_Handler();
  }
  if (HAL_UARTEx_SetRxFifoThreshold(&huart2, UART_RXFIFO_THRESHOLD_1_8) != HAL_OK)
  {
    Error_Handler();
  }
  if (HAL_UARTEx_DisableFifoMode(&huart2) != HAL_OK)
  {
    Error_Handler();
  }

}

static void MX_USART3_UART_Init(void)
{

  huart3.Instance = USART3;
  huart3.Init.BaudRate = 115200;
  huart3.Init.WordLength = UART_WORDLENGTH_8B;
  huart3.Init.StopBits = UART_STOPBITS_1;
  huart3.Init.Parity = UART_PARITY_NONE;
  huart3.Init.Mode = UART_MODE_TX_RX;
  huart3.Init.HwFlowCtl = UART_HWCONTROL_NONE;
  huart3.Init.OverSampling = UART_OVERSAMPLING_16;
  huart3.Init.OneBitSampling = UART_ONE_BIT_SAMPLE_DISABLE;
  huart3.Init.ClockPrescaler = UART_PRESCALER_DIV1;
  huart3.AdvancedInit.AdvFeatureInit = UART_ADVFEATURE_NO_INIT;
  if (HAL_UART_Init(&huart3) != HAL_OK)
  {
    Error_Handler();
  }
  if (HAL_UARTEx_SetTxFifoThreshold(&huart3, UART_TXFIFO_THRESHOLD_1_8) != HAL_OK)
  {
    Error_Handler();
  }
  if (HAL_UARTEx_SetRxFifoThreshold(&huart3, UART_RXFIFO_THRESHOLD_1_8) != HAL_OK)
  {
    Error_Handler();
  }
  if (HAL_UARTEx_DisableFifoMode(&huart3) != HAL_OK)
  {
    Error_Handler();
  }

}

static void MX_RTC_Init(void)
{

  RTC_TimeTypeDef sTime = {0};
  RTC_DateTypeDef sDate = {0};

  /** Initialize RTC Only
  */
  hrtc.Instance = RTC;
  hrtc.Init.HourFormat = RTC_HOURFORMAT_24;
  hrtc.Init.AsynchPrediv = 127;
  hrtc.Init.SynchPrediv = 255;
  hrtc.Init.OutPut = RTC_OUTPUT_DISABLE;
  hrtc.Init.OutPutRemap = RTC_OUTPUT_REMAP_NONE;
  hrtc.Init.OutPutPolarity = RTC_OUTPUT_POLARITY_HIGH;
  hrtc.Init.OutPutType = RTC_OUTPUT_TYPE_OPENDRAIN;
  hrtc.Init.BinMode = RTC_BINARY_NONE;
  if (HAL_RTC_Init(&hrtc) != HAL_OK)
  {
    Error_Handler();
  }

  /** Initialize RTC and set the Time and Date
  */
  sTime.Hours = 0x0;
  sTime.Minutes = 0x0;
  sTime.Seconds = 0x0;
  sTime.DayLightSaving = RTC_DAYLIGHTSAVING_NONE;
  sTime.StoreOperation = RTC_STOREOPERATION_RESET;
  if (HAL_RTC_SetTime(&hrtc, &sTime, RTC_FORMAT_BCD) != HAL_OK)
  {
    Error_Handler();
  }
  sDate.WeekDay = RTC_WEEKDAY_MONDAY;
  sDate.Month = RTC_MONTH_JANUARY;
  sDate.Date = 0x1;
  sDate.Year = 0x0;

  if (HAL_RTC_SetDate(&hrtc, &sDate, RTC_FORMAT_BCD) != HAL_OK)
  {
    Error_Handler();
  }

  /** Enable the WakeUp
  */
  //if (HAL_RTCEx_SetWakeUpTimer_IT(&hrtc, 59, RTC_WAKEUPCLOCK_CK_SPRE_16BITS, 0) != HAL_OK)
  if (HAL_RTCEx_SetWakeUpTimer_IT(&hrtc, 0, RTC_WAKEUPCLOCK_CK_SPRE_16BITS, 0) != HAL_OK)
  {
    Error_Handler();
  }

}

static void MX_SPI1_Init(void)
{

  /* SPI1 parameter configuration*/
  hspi1.Instance = SPI1;
  hspi1.Init.Mode = SPI_MODE_MASTER;
  hspi1.Init.Direction = SPI_DIRECTION_2LINES;
  hspi1.Init.DataSize = SPI_DATASIZE_8BIT;
  hspi1.Init.CLKPolarity = SPI_POLARITY_LOW;
  hspi1.Init.CLKPhase = SPI_PHASE_1EDGE;
  hspi1.Init.NSS = SPI_NSS_SOFT;
  hspi1.Init.BaudRatePrescaler = SPI_BAUDRATEPRESCALER_256;
  hspi1.Init.FirstBit = SPI_FIRSTBIT_MSB;
  hspi1.Init.TIMode = SPI_TIMODE_DISABLE;
  hspi1.Init.CRCCalculation = SPI_CRCCALCULATION_DISABLE;
  hspi1.Init.CRCPolynomial = 7;
  hspi1.Init.CRCLength = SPI_CRC_LENGTH_DATASIZE;
  hspi1.Init.NSSPMode = SPI_NSS_PULSE_ENABLE;
  if (HAL_SPI_Init(&hspi1) != HAL_OK)
  {
    Error_Handler();
  }

}

static void MX_TIM3_Init(void)
{

  TIM_ClockConfigTypeDef sClockSourceConfig = {0};
  TIM_MasterConfigTypeDef sMasterConfig = {0};

  htim3.Instance = TIM3;
  htim3.Init.Prescaler = 63999;
  htim3.Init.CounterMode = TIM_COUNTERMODE_UP;
  htim3.Init.Period = 4999;
  htim3.Init.ClockDivision = TIM_CLOCKDIVISION_DIV1;
  htim3.Init.AutoReloadPreload = TIM_AUTORELOAD_PRELOAD_DISABLE;
  if (HAL_TIM_Base_Init(&htim3) != HAL_OK)
  {
    Error_Handler();
  }
  sClockSourceConfig.ClockSource = TIM_CLOCKSOURCE_INTERNAL;
  if (HAL_TIM_ConfigClockSource(&htim3, &sClockSourceConfig) != HAL_OK)
  {
    Error_Handler();
  }
  if (HAL_TIM_OnePulse_Init(&htim3, TIM_OPMODE_SINGLE) != HAL_OK)
  {
    Error_Handler();
  }
  sMasterConfig.MasterOutputTrigger = TIM_TRGO_RESET;
  sMasterConfig.MasterSlaveMode = TIM_MASTERSLAVEMODE_DISABLE;
  if (HAL_TIMEx_MasterConfigSynchronization(&htim3, &sMasterConfig) != HAL_OK)
  {
    Error_Handler();
  }

}

static void MX_TIM6_Init(void)
{

  TIM_MasterConfigTypeDef sMasterConfig = {0};

  htim6.Instance = TIM6;
  htim6.Init.Prescaler = 63999;
  htim6.Init.CounterMode = TIM_COUNTERMODE_UP;
  htim6.Init.Period = 99;
  htim6.Init.AutoReloadPreload = TIM_AUTORELOAD_PRELOAD_DISABLE;
  if (HAL_TIM_Base_Init(&htim6) != HAL_OK)
  {
    Error_Handler();
  }
  sMasterConfig.MasterOutputTrigger = TIM_TRGO_RESET;
  sMasterConfig.MasterSlaveMode = TIM_MASTERSLAVEMODE_DISABLE;
  if (HAL_TIMEx_MasterConfigSynchronization(&htim6, &sMasterConfig) != HAL_OK)
  {
    Error_Handler();
  }

}

static void MX_DMA_Init(void)
{

  /* DMA controller clock enable */
  __HAL_RCC_DMAMUX1_CLK_ENABLE();
  __HAL_RCC_DMA2_CLK_ENABLE();

  /* DMA interrupt init */
  /* DMA2_Channel1_IRQn interrupt configuration */
  HAL_NVIC_SetPriority(DMA2_Channel1_IRQn, 0, 0);
  HAL_NVIC_EnableIRQ(DMA2_Channel1_IRQn);
  /* DMA2_Channel2_IRQn interrupt configuration */
  HAL_NVIC_SetPriority(DMA2_Channel2_IRQn, 0, 0);
  HAL_NVIC_EnableIRQ(DMA2_Channel2_IRQn);
  /* DMA2_Channel3_IRQn interrupt configuration */
  HAL_NVIC_SetPriority(DMA2_Channel3_IRQn, 0, 0);
  HAL_NVIC_EnableIRQ(DMA2_Channel3_IRQn);
  /* DMA2_Channel4_IRQn interrupt configuration */
  HAL_NVIC_SetPriority(DMA2_Channel4_IRQn, 0, 0);
  HAL_NVIC_EnableIRQ(DMA2_Channel4_IRQn);
  /* DMA2_Channel5_IRQn interrupt configuration */
  HAL_NVIC_SetPriority(DMA2_Channel5_IRQn, 0, 0);
  HAL_NVIC_EnableIRQ(DMA2_Channel5_IRQn);

}

static void MX_GPIO_Init(void)
{
    GPIO_InitTypeDef GPIO_InitStruct = {0};

    /*
     * ============================================================
     * Включение тактирования портов GPIO.
     * ============================================================
     */
    __HAL_RCC_GPIOC_CLK_ENABLE();
    __HAL_RCC_GPIOH_CLK_ENABLE();
    __HAL_RCC_GPIOA_CLK_ENABLE();
    __HAL_RCC_GPIOB_CLK_ENABLE();

    /*
     * ============================================================
     * Установка начальных уровней существующих выходов.
     * ============================================================
     */

    /* PC13 — светодиод SD-карты.
     * PC6, PC7 — управление интерфейсом RS485.
     */
    HAL_GPIO_WritePin(
        GPIOC,
        LED_Pin | RE485_Pin | DE485_Pin,
        GPIO_PIN_RESET
    );

    /* Начальный уровень CS SD-карты — высокий. */
    HAL_GPIO_WritePin(
        SD_CARD_CS_GPIO_Port,
        SD_CARD_CS_Pin,
        GPIO_PIN_SET
    );

    /* Начальный уровень сигнала сброса GPS. */
    HAL_GPIO_WritePin(
        GPS_RESET_GPIO_Port,
        GPS_RESET_Pin,
        GPIO_PIN_RESET
    );

    /*
     * ============================================================
     * НОВОЕ: начальные уровни светодиодов аккумулятора.
     *
     * PA15 — индикатор 33%.
     * PA12 — индикатор 66%.
     * PA11 — индикатор 100%.
     *
     * Логический 0 — светодиод выключен.
     * Логическая 1 — светодиод включён.
     *
     * Все три светодиода первоначально выключены.
     * ============================================================
     */
    HAL_GPIO_WritePin(
        GPIOA,
        GPIO_PIN_11 | GPIO_PIN_12 | GPIO_PIN_15,
        GPIO_PIN_RESET
    );

    /*
     * ============================================================
     * Настройка существующих выходов GPIOC.
     * ============================================================
     */
    GPIO_InitStruct.Pin = LED_Pin | RE485_Pin | DE485_Pin;
    GPIO_InitStruct.Mode = GPIO_MODE_OUTPUT_PP;
    GPIO_InitStruct.Pull = GPIO_NOPULL;
    GPIO_InitStruct.Speed = GPIO_SPEED_FREQ_LOW;
    HAL_GPIO_Init(GPIOC, &GPIO_InitStruct);

    /*
     * Настройка CS SD-карты.
     */
    GPIO_InitStruct.Pin = SD_CARD_CS_Pin;
    GPIO_InitStruct.Mode = GPIO_MODE_OUTPUT_PP;
    GPIO_InitStruct.Pull = GPIO_PULLUP;
    GPIO_InitStruct.Speed = GPIO_SPEED_FREQ_LOW;
    HAL_GPIO_Init(SD_CARD_CS_GPIO_Port, &GPIO_InitStruct);

    /*
     * Настройка PC11 как входа.
     * Существующую конфигурацию не изменяем.
     */
    GPIO_InitStruct.Pin = GPIO_PIN_11;
    GPIO_InitStruct.Mode = GPIO_MODE_INPUT;
    GPIO_InitStruct.Pull = GPIO_NOPULL;
    HAL_GPIO_Init(GPIOC, &GPIO_InitStruct);

    /*
     * Настройка выхода сброса GPS.
     */
    GPIO_InitStruct.Pin = GPS_RESET_Pin;
    GPIO_InitStruct.Mode = GPIO_MODE_OUTPUT_PP;
    GPIO_InitStruct.Pull = GPIO_NOPULL;
    GPIO_InitStruct.Speed = GPIO_SPEED_FREQ_LOW;
    HAL_GPIO_Init(GPS_RESET_GPIO_Port, &GPIO_InitStruct);

    /*
     * ============================================================
     * НОВОЕ: настройка светодиодов аккумулятора.
     *
     * PA11, PA12, PA15 — цифровые выходы.
     *
     * GPIO_MODE_OUTPUT_PP — двухтактный выход Push-Pull.
     * GPIO_NOPULL — без внутренних подтяжек.
     * GPIO_SPEED_FREQ_LOW — низкая скорость переключения.
     *
     * Настройка не затрагивает другие выводы GPIOA.
     * ============================================================
     */
    GPIO_InitStruct.Pin =
        GPIO_PIN_11 | GPIO_PIN_12 | GPIO_PIN_15;

    GPIO_InitStruct.Mode = GPIO_MODE_OUTPUT_PP;
    GPIO_InitStruct.Pull = GPIO_NOPULL;
    GPIO_InitStruct.Speed = GPIO_SPEED_FREQ_LOW;

    HAL_GPIO_Init(GPIOA, &GPIO_InitStruct);

}

/* USER CODE BEGIN 4 */

/**
 * @brief Обработка завершения приёма UART через DMA.
 *
 * Для LIDAR используется LPUART1.
 * После приёма 45 байтов управление передаётся
 * модулю lidar.c.
 */
void HAL_UART_RxCpltCallback(UART_HandleTypeDef *huart)
{
    /*
     * Проверяем, что прерывание относится именно к LPUART1.
     * Другие UART здесь не обрабатываем.
     */
    if (huart->Instance == LPUART1)
    {
        /*
         * Модуль LIDAR остановит DMA-приём
         * и установит флаг готовности lidar_info.
         */
        LIDAR_RxCpltCallback();
        return;
    }
}

/*
 * Callback секундного прерывания RTC WakeUp Timer.
 *
 * Вызывается библиотекой HAL после обработки
 * прерывания RTC_WKUP_IRQHandler().
 *
 * Каждое срабатывание соответствует одной секунде.
 *
 * В прерывании выполняется только увеличение счётчика.
 * Никаких переходов состояний, запросов приборов
 * и других операций здесь нет.
 */
void HAL_RTCEx_WakeUpTimerEventCallback(RTC_HandleTypeDef *hrtc)
{
    if (hrtc->Instance == RTC) rtc_seconds++;
}

/*
 * ============================================================
 * ЗАВЕРШЕНИЕ ПРЕОБРАЗОВАНИЯ ADC1
 * ============================================================
 *
 * Вызывается HAL из прерывания ADC1 после успешного
 * завершения преобразования.
 *
 * Здесь не выполняем вычисления напряжения,
 * не запускаем следующее преобразование
 * и не изменяем состояние LOGGER.
 *
 * Только сохраняем результат и устанавливаем флаг.
 * Дальнейшая обработка выполняется в BATTERY_PROC.
 */
void HAL_ADC_ConvCpltCallback(ADC_HandleTypeDef *hadc)
{
    /*
     * Проверяем, что прерывание относится именно к ADC1.
     */
    if (hadc->Instance != ADC1)
    {
        return;
    }

    /*
     * Если рабочий цикл контроля аккумулятора
     * не активен, результат не обрабатываем.
     */
    if (battery_adc_active == 0U)
    {
        return;
    }

    /*
     * Сохраняем результат завершённого преобразования.
     */
    battery_adc_raw = (uint16_t)HAL_ADC_GetValue(hadc);

    /*
     * Сообщаем стейт-машине о готовности результата.
     */
    battery_adc_ready = 1U;
}

/*
 * ============================================================
 * ОБРАБОТКА ОШИБКИ ADC1
 * ============================================================
 *
 * Вызывается HAL при обнаружении ошибки ADC.
 *
 * Обработчик не увеличивает batt_error_counter,
 * поскольку счётчик должен увеличиваться только
 * один раз за неуспешный цикл измерения.
 *
 * Ошибка будет обработана в BATTERY_ERROR_PROC.
 */
void HAL_ADC_ErrorCallback(ADC_HandleTypeDef *hadc)
{
    /*
     * Игнорируем события других ADC.
     */
    if (hadc->Instance != ADC1)
    {
        return;
    }

    /*
     * Учитываем ошибки только во время рабочего
     * измерения аккумулятора.
     */
    if (battery_adc_active == 0U)
    {
        return;
    }

    /*
     * Регистрируем ошибку.
     *
     * Основная стейт-машина обнаружит этот флаг
     * при следующем проходе BATTERY_PROC.
     */
    battery_adc_error = 1U;
}

/* USER CODE END 4 */

void Error_Handler(void)
{
  __disable_irq();
  while (1)
  {
  }
}
